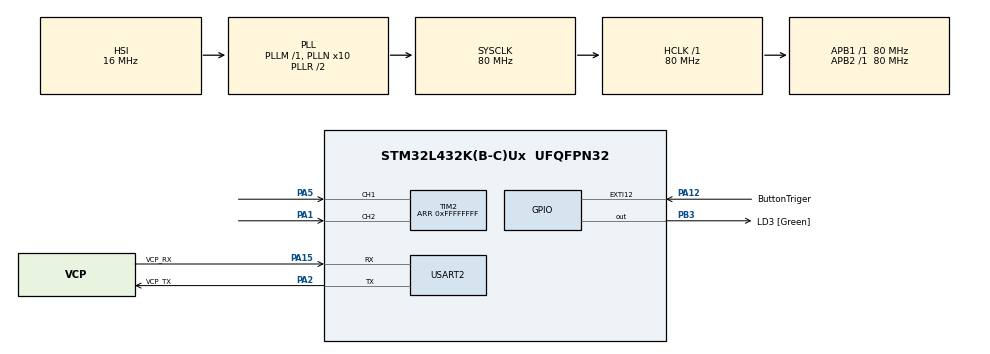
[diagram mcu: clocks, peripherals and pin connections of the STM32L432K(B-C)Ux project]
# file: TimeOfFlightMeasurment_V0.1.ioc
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Mcu.Family=STM32L4
Mcu.Name=STM32L432K(B-C)Ux
Mcu.Package=UFQFPN32
NVIC.EXTI15_10_IRQn=true\:0\:0\:false\:false\:true\:true\:true
NVIC.PriorityGroup=NVIC_PRIORITYGROUP_4
NVIC.TIM2_IRQn=true\:0\:0\:false\:false\:true\:true\:true
PA0.GPIO_Label=MCO [High speed clock in]
PA0.Signal=RCC_CK_IN
PA1.GPIO_ModeDefaultPP=GPIO_MODE_AF_OD
PA1.GPIO_Speed=GPIO_SPEED_FREQ_VERY_HIGH
PA1.Signal=S_TIM2_CH2
PA12.GPIO_Label=ButtonTriger
PA12.GPIO_PuPd=GPIO_PULLUP
PA12.Signal=GPXTI12
PA13\ (JTMS-SWDIO).GPIO_Label=SWDIO
PA13\ (JTMS-SWDIO).Mode=Serial_Wire
PA13\ (JTMS-SWDIO).Signal=SYS_JTMS-SWDIO
PA14\ (JTCK-SWCLK).GPIO_Label=SWCLK
PA14\ (JTCK-SWCLK).Mode=Serial_Wire
PA14\ (JTCK-SWCLK).Signal=SYS_JTCK-SWCLK
PA15\ (JTDI).GPIO_Label=VCP_RX
PA15\ (JTDI).Mode=Asynchronous
PA15\ (JTDI).Signal=USART2_RX
PA2.GPIO_Label=VCP_TX
PA2.Mode=Asynchronous
PA2.Signal=USART2_TX
PA5.GPIO_ModeDefaultPP=GPIO_MODE_AF_OD
PA5.GPIO_Speed=GPIO_SPEED_FREQ_VERY_HIGH
PA5.Signal=S_TIM2_CH1
PB3\ (JTDO-TRACESWO).GPIO_Label=LD3 [Green]
PB3\ (JTDO-TRACESWO).Signal=GPIO_Output
PC14-OSC32_IN\ (PC14).Mode=LSE-External-Oscillator
PC14-OSC32_IN\ (PC14).Signal=RCC_OSC32_IN
PC15-OSC32_OUT\ (PC15).Mode=LSE-External-Oscillator
PC15-OSC32_OUT\ (PC15).Signal=RCC_OSC32_OUT
ProjectManager.HeapSize=0x200
ProjectManager.StackSize=0x400
ProjectManager.TargetToolchain=MDK-ARM V5.27
RCC.ADCFreq_Value=64000000
RCC.AHBFreq_Value=80000000
RCC.APB1Freq_Value=80000000
RCC.APB1TimFreq_Value=80000000
RCC.APB2Freq_Value=80000000
RCC.APB2TimFreq_Value=80000000
RCC.CortexFreq_Value=80000000
RCC.HCLKFreq_Value=80000000
RCC.HSE_VALUE=8000000
RCC.HSI16_VALUE=16000000
RCC.HSI48_VALUE=48000000
RCC.HSI_VALUE=16000000
RCC.MSIClockRange=RCC_MSIRANGE_7
RCC.MSI_VALUE=8000000
RCC.PLLMUL=RCC_PLLMUL_4
RCC.PLLN=10
RCC.PLLSourceVirtual=RCC_PLLSOURCE_HSI
RCC.SYSCLKFreq_VALUE=80000000
RCC.SYSCLKSource=RCC_SYSCLKSOURCE_PLLCLK
RCC.USBFreq_Value=64000000
RCC.VCOOutputFreq_Value=160000000
SH.S_TIM2_CH1.0=TIM2_CH1,Input_Capture1_from_TI1
SH.S_TIM2_CH2.0=TIM2_CH2,Input_Capture2_from_TI2
TIM2.Channel-Input_Capture1_from_TI1=TIM_CHANNEL_1
TIM2.Channel-Input_Capture2_from_TI2=TIM_CHANNEL_2
TIM2.Period=0xFFFFFFFF
USART2.VirtualMode-Asynchronous=VM_ASYNC
VP_TIM2_VS_ClockSourceINT.Mode=Internal
board=NUCLEO-L432KC

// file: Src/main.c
/* USER CODE BEGIN Header */
/**
  ******************************************************************************
  * @file           : main.c
  * @brief          : Main program body
  ******************************************************************************
  * @attention
  *
  * <h2><center>&copy; Copyright (c) 2020 STMicroelectronics.
  * All rights reserved.</center></h2>
  *
  * This software component is licensed by ST under BSD 3-Clause license,
  * the "License"; You may not use this file except in compliance with the
  * License. You may obtain a copy of the License at:
  *                        opensource.org/licenses/BSD-3-Clause
  *
  ******************************************************************************
  */
/* USER CODE END Header */

#include "main.h"

/* USER CODE BEGIN Includes */
#include "LCD.h"
#include <stdio.h>
/* USER CODE END Includes */

TIM_HandleTypeDef htim2;

UART_HandleTypeDef huart2;

void SystemClock_Config(void);
static void MX_GPIO_Init(void);
static void MX_USART2_UART_Init(void);
static void MX_TIM2_Init(void);
/* USER CODE BEGIN PFP */
void HAL_TIM_IC_CaptureCallback(TIM_HandleTypeDef *htim); //input capture
/* USER CODE END PFP */

/* USER CODE BEGIN 0 */
volatile uint32_t StartMeasurment = 0; // 0 no clicked button / 1 clikced start button
volatile uint32_t IC_Value1 = 0;
volatile uint32_t IC_Value2 = 0;
volatile uint32_t Difference = 0;
volatile uint8_t TimeRdyToSend = 0; //0 not rdy to send , 1 rdy to send
volatile uint8_t sChangeMode = 1; //Change mode

uint8_t Mode = CONTINOUS_MODE;
double MicroTime = 0;
double Speed = 0;
double GateRange = 12.5;
/* USER CODE END 0 */

int main(void)
{

  /* MCU Configuration--------------------------------------------------------*/

  /* Reset of all peripherals, Initializes the Flash interface and the Systick. */
  HAL_Init();

  /* Configure the system clock */
  SystemClock_Config();

  /* Initialize all configured peripherals */
  MX_GPIO_Init();
  MX_USART2_UART_Init();
  MX_TIM2_Init();
  /* USER CODE BEGIN 2 */
	LCD_Init();
	LCD_Puts(0,0,"Cruising speed:");
	LCD_Puts(0,1,"0.0");
	LCD_Puts(13,1,"M/S");
	//HAL_TIM_IC_Start_IT(&htim2,TIM_CHANNEL_1);
	//HAL_TIM_IC_Start_IT(&htim2,TIM_CHANNEL_2);
  /* USER CODE END 2 */

  /* Infinite loop */
  while (1)
  {

    /* USER CODE BEGIN 3 */
		if (TimeRdyToSend )
		{
			uint8_t n;
			uint8_t buffer [14];
			MicroTime = Difference*(1000000.0/SystemCoreClock);
			Speed = 10000*GateRange/MicroTime;
			n = sprintf((char*)buffer,"%.6E",Speed);
			LCD_Clear();
			LCD_Puts(0,0,"Cruising speed:");
			LCD_Puts(0,1,"0.0");
			LCD_Puts(13,1,"M/S");
			LCD_Puts(0,1,(char*)buffer);
			buffer[12] = 10;
			buffer[13] = 13;
			HAL_UART_Transmit(&huart2,buffer,n+2,10);
			IC_Value1 = 0;
			IC_Value2 = 0;
			TimeRdyToSend = 0;
			__HAL_TIM_SetCounter(&htim2,0);
			//HAL_TIM_IC_Start_IT(&htim2,TIM_CHANNEL_1);
			//HAL_TIM_IC_Start_IT(&htim2,TIM_CHANNEL_2);
		}
		else if(StartMeasurment)
		{
			LCD_Clear();
			HAL_TIM_IC_Start_IT(&htim2,TIM_CHANNEL_1);
			HAL_TIM_IC_Start_IT(&htim2,TIM_CHANNEL_2);
			LCD_Puts(0,0,"Oczekiwanie na");
			LCD_Puts(0,1,"pocisk...");
			StartMeasurment = 0;
		}
		else if (sChangeMode)
		{
			if (Mode == CONTINOUS_MODE)
			{
				HAL_GPIO_WritePin(LD_Mode_GPIO_Port,LD_Mode_Pin,GPIO_PIN_SET);
				Mode = DISCONTINOUS_MODE;
				sChangeMode = 0;
			}
			else
			{
				HAL_GPIO_WritePin(LD_Mode_GPIO_Port,LD_Mode_Pin,GPIO_PIN_RESET);
				Mode = CONTINOUS_MODE;
				sChangeMode = 0;
			}
		}
  }
  /* USER CODE END 3 */
}

void SystemClock_Config(void)
{
  RCC_OscInitTypeDef RCC_OscInitStruct = {0};
  RCC_ClkInitTypeDef RCC_ClkInitStruct = {0};
  RCC_PeriphCLKInitTypeDef PeriphClkInit = {0};

  /** Initializes the CPU, AHB and APB busses clocks
  */
  RCC_OscInitStruct.OscillatorType = RCC_OSCILLATORTYPE_HSI;
  RCC_OscInitStruct.HSIState = RCC_HSI_ON;
  RCC_OscInitStruct.HSICalibrationValue = RCC_HSICALIBRATION_DEFAULT;
  RCC_OscInitStruct.PLL.PLLState = RCC_PLL_ON;
  RCC_OscInitStruct.PLL.PLLSource = RCC_PLLSOURCE_HSI;
  RCC_OscInitStruct.PLL.PLLM = 1;
  RCC_OscInitStruct.PLL.PLLN = 10;
  RCC_OscInitStruct.PLL.PLLP = RCC_PLLP_DIV7;
  RCC_OscInitStruct.PLL.PLLQ = RCC_PLLQ_DIV2;
  RCC_OscInitStruct.PLL.PLLR = RCC_PLLR_DIV2;
  if (HAL_RCC_OscConfig(&RCC_OscInitStruct) != HAL_OK)
  {
    Error_Handler();
  }
  /** Initializes the CPU, AHB and APB busses clocks
  */
  RCC_ClkInitStruct.ClockType = RCC_CLOCKTYPE_HCLK|RCC_CLOCKTYPE_SYSCLK
                              |RCC_CLOCKTYPE_PCLK1|RCC_CLOCKTYPE_PCLK2;
  RCC_ClkInitStruct.SYSCLKSource = RCC_SYSCLKSOURCE_PLLCLK;
  RCC_ClkInitStruct.AHBCLKDivider = RCC_SYSCLK_DIV1;
  RCC_ClkInitStruct.APB1CLKDivider = RCC_HCLK_DIV1;
  RCC_ClkInitStruct.APB2CLKDivider = RCC_HCLK_DIV1;

  if (HAL_RCC_ClockConfig(&RCC_ClkInitStruct, FLASH_LATENCY_4) != HAL_OK)
  {
    Error_Handler();
  }
  PeriphClkInit.PeriphClockSelection = RCC_PERIPHCLK_USART2;
  PeriphClkInit.Usart2ClockSelection = RCC_USART2CLKSOURCE_PCLK1;
  if (HAL_RCCEx_PeriphCLKConfig(&PeriphClkInit) != HAL_OK)
  {
    Error_Handler();
  }
  /** Configure the main internal regulator output voltage
  */
  if (HAL_PWREx_ControlVoltageScaling(PWR_REGULATOR_VOLTAGE_SCALE1) != HAL_OK)
  {
    Error_Handler();
  }
}

static void MX_TIM2_Init(void)
{

  TIM_ClockConfigTypeDef sClockSourceConfig = {0};
  TIM_MasterConfigTypeDef sMasterConfig = {0};
  TIM_IC_InitTypeDef sConfigIC = {0};

  htim2.Instance = TIM2;
  htim2.Init.Prescaler = 0;
  htim2.Init.CounterMode = TIM_COUNTERMODE_UP;
  htim2.Init.Period = 0xFFFFFFFF;
  htim2.Init.ClockDivision = TIM_CLOCKDIVISION_DIV1;
  htim2.Init.AutoReloadPreload = TIM_AUTORELOAD_PRELOAD_DISABLE;
  if (HAL_TIM_Base_Init(&htim2) != HAL_OK)
  {
    Error_Handler();
  }
  sClockSourceConfig.ClockSource = TIM_CLOCKSOURCE_INTERNAL;
  if (HAL_TIM_ConfigClockSource(&htim2, &sClockSourceConfig) != HAL_OK)
  {
    Error_Handler();
  }
  if (HAL_TIM_IC_Init(&htim2) != HAL_OK)
  {
    Error_Handler();
  }
  sMasterConfig.MasterOutputTrigger = TIM_TRGO_RESET;
  sMasterConfig.MasterSlaveMode = TIM_MASTERSLAVEMODE_DISABLE;
  if (HAL_TIMEx_MasterConfigSynchronization(&htim2, &sMasterConfig) != HAL_OK)
  {
    Error_Handler();
  }
  sConfigIC.ICPolarity = TIM_INPUTCHANNELPOLARITY_RISING;
  sConfigIC.ICSelection = TIM_ICSELECTION_DIRECTTI;
  sConfigIC.ICPrescaler = TIM_ICPSC_DIV1;
  sConfigIC.ICFilter = 0;
  if (HAL_TIM_IC_ConfigChannel(&htim2, &sConfigIC, TIM_CHANNEL_1) != HAL_OK)
  {
    Error_Handler();
  }
  if (HAL_TIM_IC_ConfigChannel(&htim2, &sConfigIC, TIM_CHANNEL_2) != HAL_OK)
  {
    Error_Handler();
  }

}

static void MX_USART2_UART_Init(void)
{

  huart2.Instance = USART2;
  huart2.Init.BaudRate = 115200;
  huart2.Init.WordLength = UART_WORDLENGTH_8B;
  huart2.Init.StopBits = UART_STOPBITS_1;
  huart2.Init.Parity = UART_PARITY_NONE;
  huart2.Init.Mode = UART_MODE_TX_RX;
  huart2.Init.HwFlowCtl = UART_HWCONTROL_NONE;
  huart2.Init.OverSampling = UART_OVERSAMPLING_16;
  huart2.Init.OneBitSampling = UART_ONE_BIT_SAMPLE_DISABLE;
  huart2.AdvancedInit.AdvFeatureInit = UART_ADVFEATURE_NO_INIT;
  if (HAL_UART_Init(&huart2) != HAL_OK)
  {
    Error_Handler();
  }

}

static void MX_GPIO_Init(void)
{
  GPIO_InitTypeDef GPIO_InitStruct = {0};

  /* GPIO Ports Clock Enable */
  __HAL_RCC_GPIOC_CLK_ENABLE();
  __HAL_RCC_GPIOA_CLK_ENABLE();
  __HAL_RCC_GPIOB_CLK_ENABLE();

  /*Configure GPIO pin Output Level */
  HAL_GPIO_WritePin(LD_Mode_GPIO_Port, LD_Mode_Pin, GPIO_PIN_RESET);

  /*Configure GPIO pin : ButtonTriger_Pin */
  GPIO_InitStruct.Pin = ButtonTriger_Pin;
  GPIO_InitStruct.Mode = GPIO_MODE_IT_RISING;
  GPIO_InitStruct.Pull = GPIO_PULLUP;
  HAL_GPIO_Init(ButtonTriger_GPIO_Port, &GPIO_InitStruct);

  /*Configure GPIO pin : LD_Mode_Pin */
  GPIO_InitStruct.Pin = LD_Mode_Pin;
  GPIO_InitStruct.Mode = GPIO_MODE_OUTPUT_PP;
  GPIO_InitStruct.Pull = GPIO_NOPULL;
  GPIO_InitStruct.Speed = GPIO_SPEED_FREQ_LOW;
  HAL_GPIO_Init(LD_Mode_GPIO_Port, &GPIO_InitStruct);

  /*Configure GPIO pin : Button_Mode_Pin */
  GPIO_InitStruct.Pin = Button_Mode_Pin;
  GPIO_InitStruct.Mode = GPIO_MODE_IT_RISING;
  GPIO_InitStruct.Pull = GPIO_PULLUP;
  HAL_GPIO_Init(Button_Mode_GPIO_Port, &GPIO_InitStruct);

  /* EXTI interrupt init*/
  HAL_NVIC_SetPriority(EXTI9_5_IRQn, 0, 0);
  HAL_NVIC_EnableIRQ(EXTI9_5_IRQn);

  HAL_NVIC_SetPriority(EXTI15_10_IRQn, 0, 0);
  HAL_NVIC_EnableIRQ(EXTI15_10_IRQn);

}

/* USER CODE BEGIN 4 */
void HAL_GPIO_EXTI_Callback(uint16_t GPIO_Pin){
	if (GPIO_Pin == ButtonTriger_Pin)
	{
		StartMeasurment = 1;
	}
	else if(GPIO_Pin == Button_Mode_Pin)
	{
		sChangeMode = 1;
	}
}
void HAL_TIM_IC_CaptureCallback(TIM_HandleTypeDef *htim)
{
	if(htim->Channel == HAL_TIM_ACTIVE_CHANNEL_1) //if the source is channel 1
	{
		if (IC_Value1 == 0)
				IC_Value1 = HAL_TIM_ReadCapturedValue(htim,TIM_CHANNEL_1);
	}
	else if (htim->Channel == HAL_TIM_ACTIVE_CHANNEL_2) //if the source is channel 2
	{
		if (IC_Value2 == 0)
				IC_Value2 = HAL_TIM_ReadCapturedValue(htim,TIM_CHANNEL_2);
	}

	if (IC_Value1 > IC_Value2 && IC_Value2 != 0)
	{
		Difference = IC_Value1 - IC_Value2;
		TimeRdyToSend = 1;
		HAL_TIM_IC_Stop_IT(&htim2,TIM_CHANNEL_1);
		HAL_TIM_IC_Stop_IT(&htim2,TIM_CHANNEL_2);
	}
	else if (IC_Value1 < IC_Value2 && IC_Value1 != 0)
	{
		Difference = IC_Value2 - IC_Value1;
		TimeRdyToSend = 1 ;
		HAL_TIM_IC_Stop_IT(&htim2,TIM_CHANNEL_1);
		HAL_TIM_IC_Stop_IT(&htim2,TIM_CHANNEL_2);
	}
}
/* USER CODE END 4 */

void Error_Handler(void)
{
}

/************************ (C) COPYRIGHT STMicroelectronics *****END OF FILE****/
